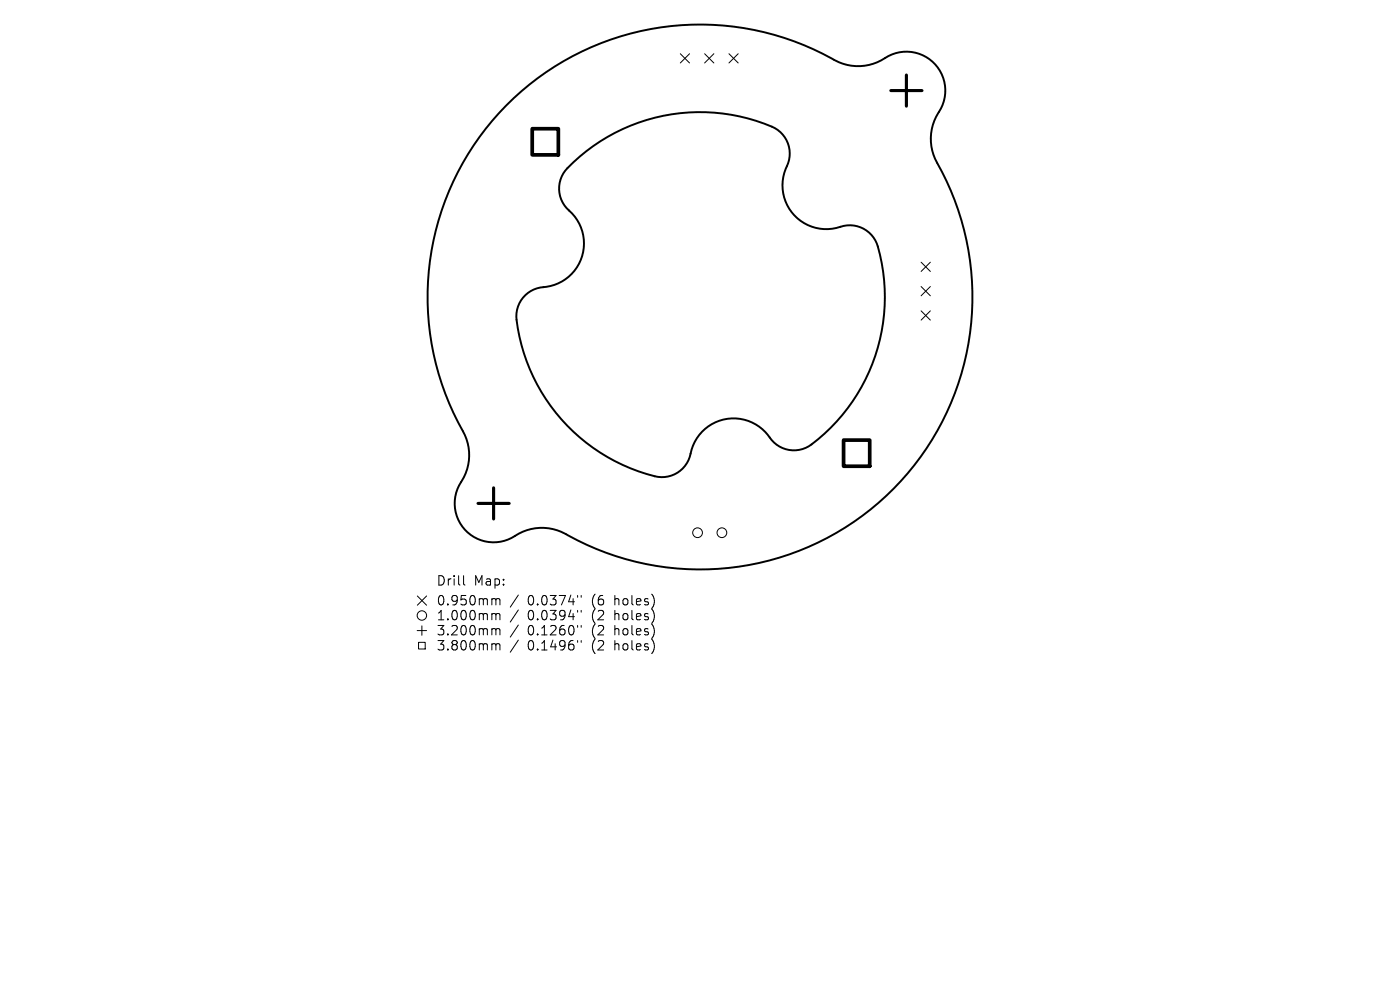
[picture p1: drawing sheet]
<svg xmlns="http://www.w3.org/2000/svg" width="297mm" height="210mm" viewBox="0 0 297 210" stroke-linecap="round" stroke-linejoin="round" font-family="sans-serif">
<defs><g id="words">
<g font-size="2.8">
<text x="92.5" y="124.5">Drill</text>
<text x="100.5" y="124.5">Map:</text>
<text x="92.5" y="128.7">0.950mm</text>
<text x="92.5" y="131.9">1.000mm</text>
<text x="111.9" y="128.7">0.0374&quot;</text>
<text x="111.9" y="131.9">0.0394&quot;</text>
<text x="125.7" y="128.7">(6</text>
<text x="125.7" y="131.9">(2</text>
<text x="130.6" y="128.7">holes)</text>
<text x="130.6" y="131.9">holes)</text>
<text x="92.5" y="135.1">3.200mm</text>
<text x="111.9" y="135.1">0.1260&quot;</text>
<text x="125.7" y="135.1">(2</text>
<text x="130.6" y="135.1">holes)</text>
<text x="92.5" y="138.3">3.800mm</text>
<text x="111.9" y="138.3">0.1496&quot;</text>
<text x="125.7" y="138.3">(2</text>
<text x="130.6" y="138.3">holes)</text>
</g>
</g></defs>
<path d="M107.4 22.4a58 58 0 0 1 70.6-9.2 10.6 10.6 0 0 0 10.5-1.3 8.3 8.3 0 0 1 10 1.9 8.3 8.3 0 0 1 .6 10.2 10.3 10.3 0 0 0-.3 10.5 57.8 57.8 0 0 1-9.9 69.8 57.8 57.8 0 0 1-69.9 8.5 10.6 10.6 0 0 0-10.5 1.3 8.3 8.3 0 0 1-10-1.9 8.3 8.3 0 0 1-.6-10.2 10.3 10.3 0 0 0 .3-10.5 57.8 57.8 0 0 1 9.2-69.1zM120.4 35.7a39.1 39.1 0 0 1 44-8.5 6.3 6.3 0 0 1 2.3 8.6 9.3 9.3 0 0 0 2.1 10.2 9.3 9.3 0 0 0 10.2 1.9 6.2 6.2 0 0 1 7.2 4.4 39.1 39.1 0 0 1-14.6 42.4 6.3 6.3 0 0 1-8.7-2.4 9.3 9.3 0 0 0-9.8-3.2 9.3 9.3 0 0 0-6.8 7.8 6.2 6.2 0 0 1-7.4 4.1 39.1 39.1 0 0 1-29.4-33.9 6.3 6.3 0 0 1 6.4-6.3 9.3 9.3 0 0 0 7.7-6.9 9.3 9.3 0 0 0-3.4-9.7 6.2 6.2 0 0 1 .2-8.5z" fill="none" stroke="#000" stroke-width=".41"/>
<g fill="none" stroke="#000" stroke-width=".21">
<path d="M144.3 11.4l2 2M146.3 11.4l-2 2M149.5 11.4l1.9 2M151.4 11.4l-1.9 2M154.6 11.4l2 2M156.6 11.4l-2 2M195.4 55.6l2 2M197.4 55.6l-2 2M195.4 60.8l2 1.9M195.4 65.9l2 2M197.4 60.8l-2 1.9M197.4 65.9l-2 2"/>
<path d="M88.5 133.8h2M88.5 126.4l2 2M88.8 136.3h1.4v1.4h-1.4zM89.5 132.8v2M90.5 126.4l-2 2M98.3 122.1v1.7l.3 .3M104.6 127l.5 .1 .1 .2M104.6 130.1l.5 .1 .1 .2M104.6 133.3l.5 .1 .1 .2M104.6 136.5h.3l.3 .3M105.2 127.3l.3-.3 .5 .1 .1 1.2M105.2 127.3v1"/>
<path d="M105.2 130.4v1.1M105.2 133.6v1.1M105.2 136.8v1.1M105.2 130.4l.3-.3 .5 .1 .1 1.3M105.2 133.6l.3-.3 .5 .1 .1 1.3M105.2 136.8l.3-.3 .5 .1 .1 1.3M110 126.2l-1.8 2.6M110 129.4l-1.8 2.6M110 132.6l-1.8 2.6M110 135.8l-1.8 2.6M122.5 126.3v.4M122.5 129.5v.4"/>
<path d="M122.5 132.7v.4M122.5 135.9v.4M123.3 126.3v.4M123.3 129.5v.4M123.3 132.7v.4M123.3 135.9v.4"/>
<circle cx="148" cy="113" r="1.03"/>
<circle cx="153.1" cy="113" r="1.03"/>
<circle cx="89.5" cy="130.6" r="1"/>
</g>
<path d="M189 19.2h6.6M192.3 15.9v6.6M101.4 106.8h6.6M104.7 103.5v6.6" fill="none" stroke="#000" stroke-width=".66"/>
<path d="M112.9 27.3h5.6v5.6h-5.6zM179 93.4h5.5v5.5h-5.5z" fill="none" stroke="#000" stroke-width=".78"/>
<use href="#words"/>
</svg>
